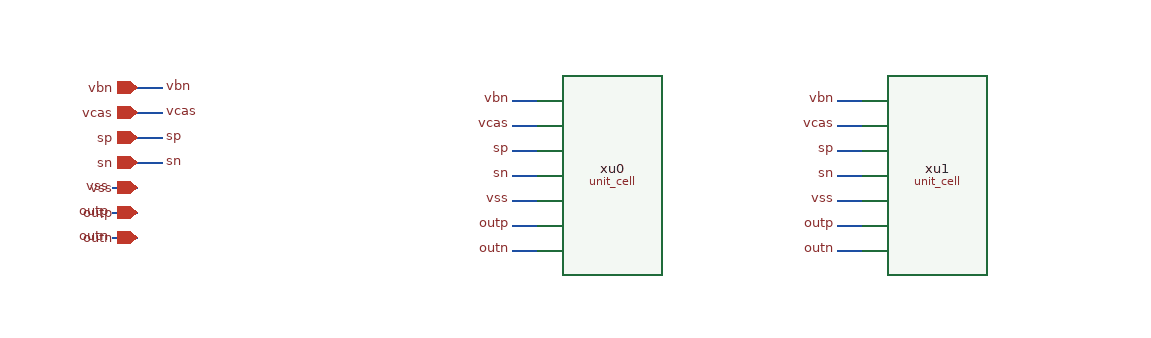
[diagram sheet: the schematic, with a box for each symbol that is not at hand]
v {xschem version=3.4.4 file_version=1.2
}
G {}
V {}
S {}
E {}
C {unit_cell.sym} 0 0 0 0 {name=xu0}
N -80 10 -100 10 {}
C {devices/lab_pin.sym} -100 10 0 0 {name=l1 sig_type=std_logic lab=vbn}
N -80 30 -100 30 {}
C {devices/lab_pin.sym} -100 30 0 0 {name=l2 sig_type=std_logic lab=vcas}
N -80 50 -100 50 {}
C {devices/lab_pin.sym} -100 50 0 0 {name=l3 sig_type=std_logic lab=sp}
N -80 70 -100 70 {}
C {devices/lab_pin.sym} -100 70 0 0 {name=l4 sig_type=std_logic lab=sn}
N -80 90 -100 90 {}
C {devices/lab_pin.sym} -100 90 0 0 {name=l5 sig_type=std_logic lab=vss}
N -80 110 -100 110 {}
C {devices/lab_pin.sym} -100 110 0 0 {name=l6 sig_type=std_logic lab=outp}
N -80 130 -100 130 {}
C {devices/lab_pin.sym} -100 130 0 0 {name=l7 sig_type=std_logic lab=outn}
C {unit_cell.sym} 260 0 0 0 {name=xu1}
N 180 10 160 10 {}
C {devices/lab_pin.sym} 160 10 0 0 {name=l8 sig_type=std_logic lab=vbn}
N 180 30 160 30 {}
C {devices/lab_pin.sym} 160 30 0 0 {name=l9 sig_type=std_logic lab=vcas}
N 180 50 160 50 {}
C {devices/lab_pin.sym} 160 50 0 0 {name=l10 sig_type=std_logic lab=sp}
N 180 70 160 70 {}
C {devices/lab_pin.sym} 160 70 0 0 {name=l11 sig_type=std_logic lab=sn}
N 180 90 160 90 {}
C {devices/lab_pin.sym} 160 90 0 0 {name=l12 sig_type=std_logic lab=vss}
N 180 110 160 110 {}
C {devices/lab_pin.sym} 160 110 0 0 {name=l13 sig_type=std_logic lab=outp}
N 180 130 160 130 {}
C {devices/lab_pin.sym} 160 130 0 0 {name=l14 sig_type=std_logic lab=outn}
C {devices/ipin.sym} -400 0 0 0 {name=p15 lab=vbn}
N -400 0 -380 0 {}
C {devices/lab_pin.sym} -380 0 2 0 {name=l16 sig_type=std_logic lab=vbn}
C {devices/ipin.sym} -400 20 0 0 {name=p17 lab=vcas}
N -400 20 -380 20 {}
C {devices/lab_pin.sym} -380 20 2 0 {name=l18 sig_type=std_logic lab=vcas}
C {devices/ipin.sym} -400 40 0 0 {name=p19 lab=sp}
N -400 40 -380 40 {}
C {devices/lab_pin.sym} -380 40 2 0 {name=l20 sig_type=std_logic lab=sp}
C {devices/ipin.sym} -400 60 0 0 {name=p21 lab=sn}
N -400 60 -380 60 {}
C {devices/lab_pin.sym} -380 60 2 0 {name=l22 sig_type=std_logic lab=sn}
C {devices/iopin.sym} -400 80 0 0 {name=p23 lab=vss}
N -400 80 -420 80 {}
C {devices/lab_pin.sym} -420 80 0 0 {name=l24 sig_type=std_logic lab=vss}
C {devices/iopin.sym} -400 100 0 0 {name=p25 lab=outp}
N -400 100 -420 100 {}
C {devices/lab_pin.sym} -420 100 0 0 {name=l26 sig_type=std_logic lab=outp}
C {devices/iopin.sym} -400 120 0 0 {name=p27 lab=outn}
N -400 120 -420 120 {}
C {devices/lab_pin.sym} -420 120 0 0 {name=l28 sig_type=std_logic lab=outn}
